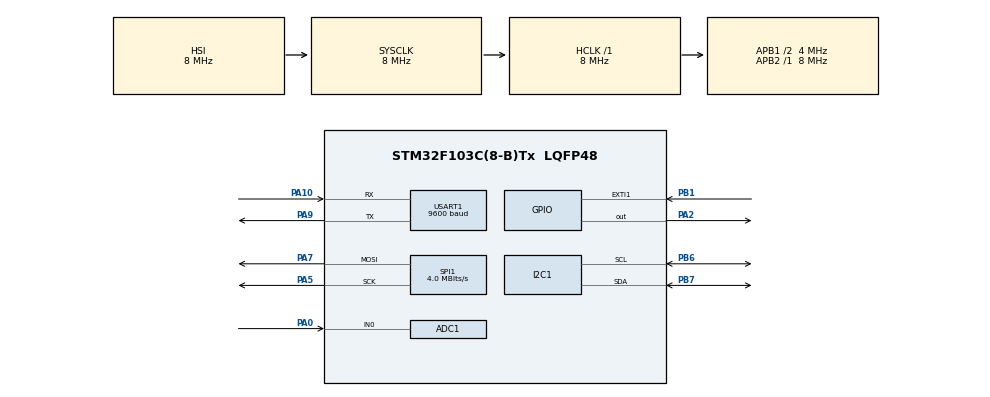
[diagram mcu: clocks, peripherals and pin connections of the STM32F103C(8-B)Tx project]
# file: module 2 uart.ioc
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ADC1.Channel-1\#ChannelRegularConversion=ADC_CHANNEL_0
ADC1.NbrOfConversionFlag=1
ADC1.Rank-1\#ChannelRegularConversion=1
ADC1.SamplingTime-1\#ChannelRegularConversion=ADC_SAMPLETIME_1CYCLE_5
ADC1.master=1
Dma.Request0=USART1_RX
Dma.USART1_RX.0.Direction=DMA_PERIPH_TO_MEMORY
Dma.USART1_RX.0.Instance=DMA1_Channel5
Dma.USART1_RX.0.MemDataAlignment=DMA_MDATAALIGN_BYTE
Dma.USART1_RX.0.MemInc=DMA_MINC_ENABLE
Dma.USART1_RX.0.Mode=DMA_NORMAL
Dma.USART1_RX.0.PeriphDataAlignment=DMA_PDATAALIGN_BYTE
Dma.USART1_RX.0.PeriphInc=DMA_PINC_DISABLE
Dma.USART1_RX.0.Priority=DMA_PRIORITY_LOW
I2C1.I2C_Mode=I2C_Fast
Mcu.Family=STM32F1
Mcu.Name=STM32F103C(8-B)Tx
Mcu.Package=LQFP48
NVIC.DMA1_Channel5_IRQn=true\:0\:0\:false\:false\:true\:false\:true\:true
NVIC.EXTI1_IRQn=true\:2\:0\:true\:false\:true\:true\:true\:true
NVIC.PriorityGroup=NVIC_PRIORITYGROUP_4
NVIC.USART1_IRQn=true\:1\:0\:true\:false\:true\:true\:true\:true
PA0-WKUP.Signal=ADCx_IN0
PA10.Mode=Asynchronous
PA10.Signal=USART1_RX
PA13.Mode=Serial_Wire
PA13.Signal=SYS_JTMS-SWDIO
PA14.Mode=Serial_Wire
PA14.Signal=SYS_JTCK-SWCLK
PA2.Signal=GPIO_Output
PA5.Mode=TX_Only_Simplex_Unidirect_Master
PA5.Signal=SPI1_SCK
PA7.Mode=TX_Only_Simplex_Unidirect_Master
PA7.Signal=SPI1_MOSI
PA9.Mode=Asynchronous
PA9.Signal=USART1_TX
PB1.GPIO_ModeDefaultEXTI=GPIO_MODE_IT_FALLING
PB1.Signal=GPXTI1
PB6.Mode=I2C
PB6.Signal=I2C1_SCL
PB7.Mode=I2C
PB7.Signal=I2C1_SDA
PD0-OSC_IN.Mode=HSE-External-Oscillator
PD0-OSC_IN.Signal=RCC_OSC_IN
PD1-OSC_OUT.Mode=HSE-External-Oscillator
PD1-OSC_OUT.Signal=RCC_OSC_OUT
ProjectManager.HeapSize=0x200
ProjectManager.StackSize=0x400
ProjectManager.TargetToolchain=MDK-ARM V5.32
RCC.ADCPresc=RCC_ADCPCLK2_DIV6
RCC.AHBFreq_Value=8000000
RCC.APB1CLKDivider=RCC_HCLK_DIV2
RCC.APB1Freq_Value=4000000
RCC.APB1TimFreq_Value=8000000
RCC.APB2Freq_Value=8000000
RCC.APB2TimFreq_Value=8000000
RCC.HCLKFreq_Value=8000000
RCC.PLLMUL=RCC_PLL_MUL9
RCC.PLLSourceVirtual=RCC_PLLSOURCE_HSE
RCC.RTCClockSelection=RCC_RTCCLKSOURCE_HSE_DIV128
RCC.SYSCLKFreq_VALUE=8000000
RCC.USBFreq_Value=72000000
SH.ADCx_IN0.0=ADC1_IN0,IN0
SPI1.BaudRatePrescaler=SPI_BAUDRATEPRESCALER_2
SPI1.CalculateBaudRate=4.0 MBits/s
SPI1.Direction=SPI_DIRECTION_2LINES
SPI1.Mode=SPI_MODE_MASTER
SPI1.VirtualType=VM_MASTER
USART1.BaudRate=9600
USART1.VirtualMode=VM_ASYNC
VP_RTC_No_RTC_Output.Mode=RTC_OUT_NO
VP_RTC_VS_RTC_Activate.Mode=RTC_Enabled
VP_RTC_VS_RTC_Calendar.Mode=RTC_Calendar
VP_TIM1_VS_ClockSourceINT.Mode=Internal
board=custom

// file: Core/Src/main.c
#include "main.h"
#include "stdio.h"
#include "string.h"
#include "max7219.h"
#include "EEPROM.h"
ADC_HandleTypeDef hadc1;

I2C_HandleTypeDef hi2c1;

RTC_HandleTypeDef hrtc;
DMA_HandleTypeDef hdma_usart1_rx;
SPI_HandleTypeDef hspi1;
SPI_HandleTypeDef hspi2;

TIM_HandleTypeDef htim1;

UART_HandleTypeDef huart1;
uint8_t aRxBuffer[100];
/* USER CODE BEGIN PV */
uint32_t adc_value = 0;
  float temperature = 0;
  char temp_str[10];
/* USER CODE END PV */

void SystemClock_Config(void);
static void MX_GPIO_Init(void);
static void MX_USART1_UART_Init(void);
static void MX_I2C1_Init(void);
static void MX_RTC_Init(void);
static void MX_SPI1_Init(void);
static void MX_TIM1_Init(void);
static void MX_ADC1_Init(void);

void toggle_led(void)
{
  HAL_GPIO_TogglePin(GPIOB, GPIO_PIN_3);
	HAL_GPIO_TogglePin(GPIOB, GPIO_PIN_4);
}

void run_adc(void){
// Start ADC conversion
    HAL_ADC_Start(&hadc1);
    // Wait for the end of conversion
    if (HAL_ADC_PollForConversion(&hadc1, HAL_MAX_DELAY) == HAL_OK)
    {
      // Get the ADC value
      adc_value = HAL_ADC_GetValue(&hadc1);
      // Convert ADC value to temperature
     float temp_float = ((float)adc_value) * 5 / 4095 * 100;

        // Convert temperature to integer
        int temperature_int = (int)(temp_float + 0.5);  // Round to the nearest integer

        // Format the temperature as a string
        sprintf(temp_str, "%d\n\r", temperature_int);
      // Transmit the temperature string via UART
      HAL_UART_Transmit(&huart1, (uint8_t*)temp_str, strlen(temp_str), HAL_MAX_DELAY);
    }
    // Stop ADC conversion
    HAL_ADC_Stop(&hadc1);
    // Wait for a while before the next reading
    HAL_Delay(1000);
}

void display_time(void)
{

    RTC_TimeTypeDef sTime;
    RTC_DateTypeDef sDate;

    // Ð?c th?i gian hi?n t?i t? RTC
    HAL_RTC_GetTime(&hrtc, &sTime, RTC_FORMAT_BIN);
    HAL_RTC_GetDate(&hrtc, &sDate, RTC_FORMAT_BIN);

    // Hi?n th? th?i gian HH:MM:SS lên LED 7 do?n
    max7219_SendData(1, sTime.Seconds % 10);           // Hàng don v? giây
    max7219_SendData(2, sTime.Seconds / 10);           // Hàng ch?c giây
    max7219_SendData(3, sTime.Minutes % 10);           // Hàng don v? phút
    max7219_SendData(4, sTime.Minutes / 10);           // Hàng ch?c phút
    max7219_SendData(5, sTime.Hours % 10);             // Hàng don v? gi?
    max7219_SendData(6, sTime.Hours / 10);             // Hàng ch?c gi?
}

void retrieve_last_temperature(void) {
    int last_temperature_int;

    // Read the last saved temperature from EEPROM at address 0x0000
    EEPROM_Read(0, 0, (uint8_t*)&last_temperature_int, sizeof(last_temperature_int));

    // Optionally, you can transmit this value via UART or display it
    sprintf(temp_str, "Last Temp: %d\n\r", last_temperature_int);
    HAL_UART_Transmit(&huart1, (uint8_t*)temp_str, strlen(temp_str), HAL_MAX_DELAY);
}

int main(void)
{
 HAL_Init();
	SystemClock_Config();
MX_GPIO_Init();
  MX_USART1_UART_Init();
  MX_I2C1_Init();
  MX_RTC_Init();
  MX_SPI1_Init();
  MX_TIM1_Init();
  MX_ADC1_Init();

		max7219_Init_16SEG(7);
    max7219_Decode_On();

	uint8_t aRxBuffer[100]; // Kích thu?c buffer ph?i phù h?p v?i c?u hình DMA

    // Kh?i t?o UART v?i DMA
	    retrieve_last_temperature();

//  //I2C_Master_Init(100000);
//  unsigned int Address = 0x0020; // Some Random Address
//  // Some Random Data BufferTo Write
//  unsigned char Buffer[5] = {0x05, 0x06, 0x07, 0x08, 0x09};
//  unsigned char ReadBuffer[5];
//
//// Write data to EEPROM
//    EEPROM_Write(3, 0, Buffer, 5);
//    HAL_Delay(10);  // Wait for the write operation to complete
//
//    // Read data back from EEPROM
//    EEPROM_Read(3, 0, ReadBuffer, 5);

//    // Optionally, transmit the read data over UART for debugging purposes
//    for (int i = 0; i < 5; i++)
//    {
//        char msg[10];
//        sprintf(msg, "Data: %d\n\r", ReadBuffer[i]);
//        HAL_UART_Transmit(&huart1, (uint8_t*)msg, strlen(msg), HAL_MAX_DELAY);
//        HAL_Delay(1000);  // Delay between transmissions
//    }
uint8_t rx_data;
	uint8_t tx_data[20]="STM32 Hello !!\r\n";
  while (1)
  {
    /* USER CODE END WHILE */
//		HAL_UART_Receive_IT(&huart1, &rx_data, 1);
//		HAL_UART_Transmit(&huart1,tx_data, sizeof(tx_data), 100);
//run_adc();
		display_time();     // Hi?n th? th?i gian
		//toggle_led();
//        HAL_Delay(1000);
  }
}

void SystemClock_Config(void)
{
  RCC_OscInitTypeDef RCC_OscInitStruct = {0};
  RCC_ClkInitTypeDef RCC_ClkInitStruct = {0};
  RCC_PeriphCLKInitTypeDef PeriphClkInit = {0};

  /** Initializes the RCC Oscillators according to the specified parameters
  * in the RCC_OscInitTypeDef structure.
  */
  RCC_OscInitStruct.OscillatorType = RCC_OSCILLATORTYPE_HSI|RCC_OSCILLATORTYPE_HSE;
  RCC_OscInitStruct.HSEState = RCC_HSE_ON;
  RCC_OscInitStruct.HSIState = RCC_HSI_ON;
  RCC_OscInitStruct.HSICalibrationValue = RCC_HSICALIBRATION_DEFAULT;
  RCC_OscInitStruct.PLL.PLLState = RCC_PLL_NONE;
  if (HAL_RCC_OscConfig(&RCC_OscInitStruct) != HAL_OK)
  {
    Error_Handler();
  }

  /** Initializes the CPU, AHB and APB buses clocks
  */
  RCC_ClkInitStruct.ClockType = RCC_CLOCKTYPE_HCLK|RCC_CLOCKTYPE_SYSCLK
                              |RCC_CLOCKTYPE_PCLK1|RCC_CLOCKTYPE_PCLK2;
  RCC_ClkInitStruct.SYSCLKSource = RCC_SYSCLKSOURCE_HSI;
  RCC_ClkInitStruct.AHBCLKDivider = RCC_SYSCLK_DIV1;
  RCC_ClkInitStruct.APB1CLKDivider = RCC_HCLK_DIV2;
  RCC_ClkInitStruct.APB2CLKDivider = RCC_HCLK_DIV1;

  if (HAL_RCC_ClockConfig(&RCC_ClkInitStruct, FLASH_LATENCY_0) != HAL_OK)
  {
    Error_Handler();
  }
  PeriphClkInit.PeriphClockSelection = RCC_PERIPHCLK_RTC|RCC_PERIPHCLK_ADC;
  PeriphClkInit.RTCClockSelection = RCC_RTCCLKSOURCE_HSE_DIV128;
  PeriphClkInit.AdcClockSelection = RCC_ADCPCLK2_DIV6;
  if (HAL_RCCEx_PeriphCLKConfig(&PeriphClkInit) != HAL_OK)
  {
    Error_Handler();
  }
}

static void MX_ADC1_Init(void)
{

  ADC_ChannelConfTypeDef sConfig = {0};

  /** Common config
  */
  hadc1.Instance = ADC1;
  hadc1.Init.ScanConvMode = ADC_SCAN_DISABLE;
  hadc1.Init.ContinuousConvMode = DISABLE;
  hadc1.Init.DiscontinuousConvMode = DISABLE;
  hadc1.Init.ExternalTrigConv = ADC_SOFTWARE_START;
  hadc1.Init.DataAlign = ADC_DATAALIGN_RIGHT;
  hadc1.Init.NbrOfConversion = 1;
  if (HAL_ADC_Init(&hadc1) != HAL_OK)
  {
    Error_Handler();
  }

  /** Configure Regular Channel
  */
  sConfig.Channel = ADC_CHANNEL_1;
  sConfig.Rank = ADC_REGULAR_RANK_1;
  sConfig.SamplingTime = ADC_SAMPLETIME_1CYCLE_5;
  if (HAL_ADC_ConfigChannel(&hadc1, &sConfig) != HAL_OK)
  {
    Error_Handler();
  }

}

static void MX_I2C1_Init(void)
{

  hi2c1.Instance = I2C1;
  hi2c1.Init.ClockSpeed = 400000;
  hi2c1.Init.DutyCycle = I2C_DUTYCYCLE_2;
  hi2c1.Init.OwnAddress1 = 0;
  hi2c1.Init.AddressingMode = I2C_ADDRESSINGMODE_7BIT;
  hi2c1.Init.DualAddressMode = I2C_DUALADDRESS_DISABLE;
  hi2c1.Init.OwnAddress2 = 0;
  hi2c1.Init.GeneralCallMode = I2C_GENERALCALL_DISABLE;
  hi2c1.Init.NoStretchMode = I2C_NOSTRETCH_DISABLE;
  if (HAL_I2C_Init(&hi2c1) != HAL_OK)
  {
    Error_Handler();
  }

}

static void MX_RTC_Init(void)
{

  RTC_TimeTypeDef sTime = {0};
  RTC_DateTypeDef DateToUpdate = {0};

  /** Initialize RTC Only
  */
  hrtc.Instance = RTC;
  hrtc.Init.AsynchPrediv = RTC_AUTO_1_SECOND;
  hrtc.Init.OutPut = RTC_OUTPUTSOURCE_NONE;
  if (HAL_RTC_Init(&hrtc) != HAL_OK)
  {
    Error_Handler();
  }

  /** Initialize RTC and set the Time and Date
  */
  sTime.Hours = 0xFF;
  sTime.Minutes = 0xFF;
  sTime.Seconds = 0xFF;

  if (HAL_RTC_SetTime(&hrtc, &sTime, RTC_FORMAT_BCD) != HAL_OK)
  {
    Error_Handler();
  }

  DateToUpdate.WeekDay = RTC_WEEKDAY_MONDAY;
  DateToUpdate.Month = RTC_MONTH_JANUARY;
  DateToUpdate.Date = 0x1;
  DateToUpdate.Year = 0x0;

  if (HAL_RTC_SetDate(&hrtc, &DateToUpdate, RTC_FORMAT_BCD) != HAL_OK)
  {
    Error_Handler();
  }

}

static void MX_SPI1_Init(void)
{

  /* SPI1 parameter configuration*/
  hspi1.Instance = SPI1;
  hspi1.Init.Mode = SPI_MODE_MASTER;
  hspi1.Init.Direction = SPI_DIRECTION_2LINES;
hspi1.Init.DataSize = SPI_DATASIZE_8BIT;
  hspi1.Init.CLKPolarity = SPI_POLARITY_LOW;
  hspi1.Init.CLKPhase = SPI_PHASE_1EDGE;
  hspi1.Init.NSS = SPI_NSS_SOFT;
  hspi1.Init.BaudRatePrescaler = SPI_BAUDRATEPRESCALER_2;
  hspi1.Init.FirstBit = SPI_FIRSTBIT_MSB;
  hspi1.Init.TIMode = SPI_TIMODE_DISABLE;
  hspi1.Init.CRCCalculation = SPI_CRCCALCULATION_DISABLE;
  hspi1.Init.CRCPolynomial = 10;
  if (HAL_SPI_Init(&hspi1) != HAL_OK)
  {
    Error_Handler();
  }

}

static void MX_SPI2_Init(void)
{

  /* SPI2 parameter configuration*/
  hspi2.Instance = SPI2;
  hspi2.Init.Mode = SPI_MODE_MASTER;
  hspi2.Init.Direction = SPI_DIRECTION_2LINES;
  hspi2.Init.DataSize = SPI_DATASIZE_8BIT;
  hspi2.Init.CLKPolarity = SPI_POLARITY_LOW;
  hspi2.Init.CLKPhase = SPI_PHASE_1EDGE;
  hspi2.Init.NSS = SPI_NSS_SOFT;
  hspi2.Init.BaudRatePrescaler = SPI_BAUDRATEPRESCALER_2;
  hspi2.Init.FirstBit = SPI_FIRSTBIT_MSB;
  hspi2.Init.TIMode = SPI_TIMODE_DISABLE;
  hspi2.Init.CRCCalculation = SPI_CRCCALCULATION_DISABLE;
  hspi2.Init.CRCPolynomial = 10;
  if (HAL_SPI_Init(&hspi2) != HAL_OK)
  {
    Error_Handler();
  }

}

static void MX_TIM1_Init(void)
{

  TIM_ClockConfigTypeDef sClockSourceConfig = {0};
  TIM_MasterConfigTypeDef sMasterConfig = {0};

  htim1.Instance = TIM1;
  htim1.Init.Prescaler = 0;
  htim1.Init.CounterMode = TIM_COUNTERMODE_UP;
  htim1.Init.Period = 65535;
  htim1.Init.ClockDivision = TIM_CLOCKDIVISION_DIV1;
  htim1.Init.RepetitionCounter = 0;
  htim1.Init.AutoReloadPreload = TIM_AUTORELOAD_PRELOAD_DISABLE;
  if (HAL_TIM_Base_Init(&htim1) != HAL_OK)
  {
    Error_Handler();
  }
  sClockSourceConfig.ClockSource = TIM_CLOCKSOURCE_INTERNAL;
  if (HAL_TIM_ConfigClockSource(&htim1, &sClockSourceConfig) != HAL_OK)
  {
    Error_Handler();
  }
  sMasterConfig.MasterOutputTrigger = TIM_TRGO_RESET;
  sMasterConfig.MasterSlaveMode = TIM_MASTERSLAVEMODE_DISABLE;
  if (HAL_TIMEx_MasterConfigSynchronization(&htim1, &sMasterConfig) != HAL_OK)
  {
    Error_Handler();
  }

}

static void MX_USART1_UART_Init(void)
{

  huart1.Instance = USART1;
  huart1.Init.BaudRate = 9600;
  huart1.Init.WordLength = UART_WORDLENGTH_8B;
  huart1.Init.StopBits = UART_STOPBITS_1;
  huart1.Init.Parity = UART_PARITY_NONE;
  huart1.Init.Mode = UART_MODE_TX_RX;
  huart1.Init.HwFlowCtl = UART_HWCONTROL_NONE;
huart1.Init.OverSampling = UART_OVERSAMPLING_16;
  if (HAL_UART_Init(&huart1) != HAL_OK)
  {
    Error_Handler();
  }
    HAL_UART_Receive_DMA(&huart1, aRxBuffer, 100);

}

void MX_DMA_Init(void)
{
    __HAL_RCC_DMA1_CLK_ENABLE();

    HAL_NVIC_SetPriority(DMA1_Channel5_IRQn, 0, 0);
    HAL_NVIC_EnableIRQ(DMA1_Channel5_IRQn);
}

static void MX_GPIO_Init(void)
{
  GPIO_InitTypeDef GPIO_InitStruct = {0};

  /* GPIO Ports Clock Enable */
  __HAL_RCC_GPIOD_CLK_ENABLE();
  __HAL_RCC_GPIOA_CLK_ENABLE();
  __HAL_RCC_GPIOB_CLK_ENABLE();

	  /*Configure GPIO pin Output Level */
  HAL_GPIO_WritePin(GPIOA, GPIO_PIN_4, GPIO_PIN_RESET);

  /*Configure GPIO pin Output Level */
  HAL_GPIO_WritePin(GPIOB, GPIO_PIN_12, GPIO_PIN_RESET);

  /*Configure GPIO pin Output Level */
  HAL_GPIO_WritePin(GPIOA, GPIO_PIN_2, GPIO_PIN_RESET);
	// Kh?i t?o GPIOA cho nút b?m
    __HAL_RCC_GPIOA_CLK_ENABLE();
    GPIO_InitStruct.Pin = GPIO_PIN_0; // Nút b?m k?t n?i v?i PA0
    GPIO_InitStruct.Mode = GPIO_MODE_INPUT;
    GPIO_InitStruct.Pull = GPIO_NOPULL;
    HAL_GPIO_Init(GPIOA, &GPIO_InitStruct);

	/*Configure GPIO pin : PA1 */
  GPIO_InitStruct.Pin = GPIO_PIN_1;
  GPIO_InitStruct.Mode = GPIO_MODE_ANALOG;
  GPIO_InitStruct.Pull = GPIO_NOPULL;
  HAL_GPIO_Init(GPIOA, &GPIO_InitStruct);

  /*Configure GPIO pin : PA2 */
  GPIO_InitStruct.Pin = GPIO_PIN_2;
  GPIO_InitStruct.Mode = GPIO_MODE_OUTPUT_PP;
  GPIO_InitStruct.Pull = GPIO_NOPULL;
  GPIO_InitStruct.Speed = GPIO_SPEED_FREQ_LOW;
  HAL_GPIO_Init(GPIOA, &GPIO_InitStruct);

  /*Configure GPIO pin : PB1 */
  GPIO_InitStruct.Pin = GPIO_PIN_1;
  GPIO_InitStruct.Mode = GPIO_MODE_IT_FALLING;
  GPIO_InitStruct.Pull = GPIO_NOPULL;
  HAL_GPIO_Init(GPIOB, &GPIO_InitStruct);

	  /*Configure GPIO pin : PA4 */
  GPIO_InitStruct.Pin = GPIO_PIN_4;
  GPIO_InitStruct.Mode = GPIO_MODE_OUTPUT_PP;
  GPIO_InitStruct.Pull = GPIO_NOPULL;
  GPIO_InitStruct.Speed = GPIO_SPEED_FREQ_LOW;
  HAL_GPIO_Init(GPIOA, &GPIO_InitStruct);

  /*Configure GPIO pin : PB0 */
  GPIO_InitStruct.Pin = GPIO_PIN_0;
  GPIO_InitStruct.Mode = GPIO_MODE_INPUT;
  GPIO_InitStruct.Pull = GPIO_NOPULL;
  HAL_GPIO_Init(GPIOB, &GPIO_InitStruct);

  /*Configure GPIO pin : PB12 */
  GPIO_InitStruct.Pin = GPIO_PIN_12;
  GPIO_InitStruct.Mode = GPIO_MODE_OUTPUT_PP;
  GPIO_InitStruct.Pull = GPIO_NOPULL;
  GPIO_InitStruct.Speed = GPIO_SPEED_FREQ_LOW;
  HAL_GPIO_Init(GPIOB, &GPIO_InitStruct);

// Configure I2C1 SDA (PB7) and SCL (PB6)
    GPIO_InitStruct.Pin = GPIO_PIN_6 | GPIO_PIN_7;
    GPIO_InitStruct.Mode = GPIO_MODE_AF_OD;
    GPIO_InitStruct.Pull = GPIO_PULLUP;
    GPIO_InitStruct.Speed = GPIO_SPEED_FREQ_HIGH;
    //GPIO_InitStruct.Alternate = GPIO_AF1_I2C1;
    HAL_GPIO_Init(GPIOB, &GPIO_InitStruct);
  /* EXTI interrupt init*/
  HAL_NVIC_SetPriority(EXTI1_IRQn, 2, 0);
  HAL_NVIC_EnableIRQ(EXTI1_IRQn);
GPIO_InitStruct.Pin = GPIO_PIN_3 | GPIO_PIN_4;
  GPIO_InitStruct.Mode = GPIO_MODE_OUTPUT_PP;
  GPIO_InitStruct.Pull = GPIO_NOPULL;
  GPIO_InitStruct.Speed = GPIO_SPEED_FREQ_LOW;
  HAL_GPIO_Init(GPIOB, &GPIO_InitStruct);

  // Optionally, set the initial state of the LEDs
  HAL_GPIO_WritePin(GPIOB, GPIO_PIN_3, GPIO_PIN_RESET);  // Turn off PB3 LED
  HAL_GPIO_WritePin(GPIOB, GPIO_PIN_4, GPIO_PIN_RESET);

}

void Error_Handler(void)
{
  __disable_irq();
  while (1)
  {
  }
}
